# Generated by FakeRAM 2.0
VERSION 5.7 ;
BUSBITCHARS "[]" ;
PROPERTYDEFINITIONS
  MACRO width INTEGER ;
  MACRO depth INTEGER ;
  MACRO banks INTEGER ;
END PROPERTYDEFINITIONS
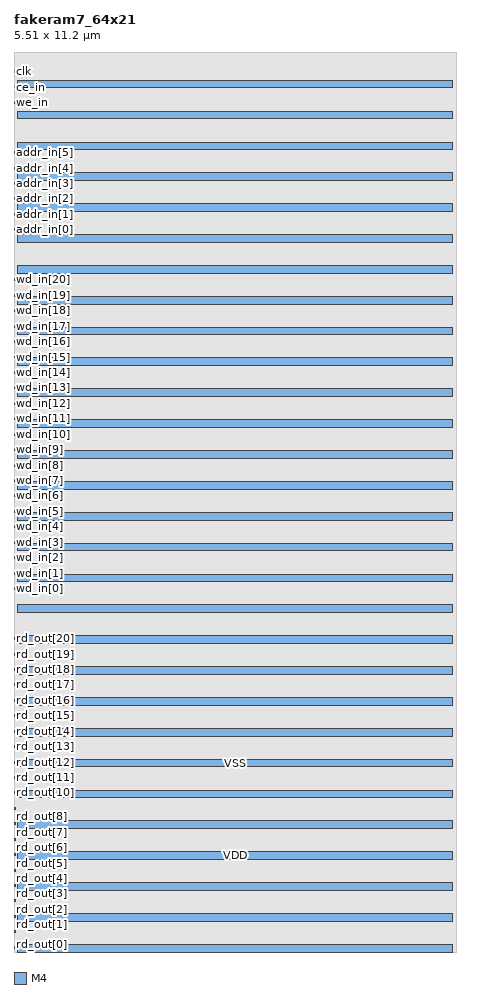
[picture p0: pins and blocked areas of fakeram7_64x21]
MACRO fakeram7_64x21
  PROPERTY width 21 ;
  PROPERTY depth 64 ;
  PROPERTY banks 2 ;
  FOREIGN fakeram7_64x21 0 0 ;
  SYMMETRY X Y R90 ;
  SIZE 5.510 BY 11.200 ;
  CLASS BLOCK ;
  PIN rd_out[0]
    DIRECTION OUTPUT ;
    USE SIGNAL ;
    SHAPE ABUTMENT ;
    PORT
      LAYER M4 ;
      RECT 0.000 0.048 0.024 0.072 ;
    END
  END rd_out[0]
  PIN rd_out[1]
    DIRECTION OUTPUT ;
    USE SIGNAL ;
    SHAPE ABUTMENT ;
    PORT
      LAYER M4 ;
      RECT 0.000 0.240 0.024 0.264 ;
    END
  END rd_out[1]
  PIN rd_out[2]
    DIRECTION OUTPUT ;
    USE SIGNAL ;
    SHAPE ABUTMENT ;
    PORT
      LAYER M4 ;
      RECT 0.000 0.432 0.024 0.456 ;
    END
  END rd_out[2]
  PIN rd_out[3]
    DIRECTION OUTPUT ;
    USE SIGNAL ;
    SHAPE ABUTMENT ;
    PORT
      LAYER M4 ;
      RECT 0.000 0.624 0.024 0.648 ;
    END
  END rd_out[3]
  PIN rd_out[4]
    DIRECTION OUTPUT ;
    USE SIGNAL ;
    SHAPE ABUTMENT ;
    PORT
      LAYER M4 ;
      RECT 0.000 0.816 0.024 0.840 ;
    END
  END rd_out[4]
  PIN rd_out[5]
    DIRECTION OUTPUT ;
    USE SIGNAL ;
    SHAPE ABUTMENT ;
    PORT
      LAYER M4 ;
      RECT 0.000 1.008 0.024 1.032 ;
    END
  END rd_out[5]
  PIN rd_out[6]
    DIRECTION OUTPUT ;
    USE SIGNAL ;
    SHAPE ABUTMENT ;
    PORT
      LAYER M4 ;
      RECT 0.000 1.200 0.024 1.224 ;
    END
  END rd_out[6]
  PIN rd_out[7]
    DIRECTION OUTPUT ;
    USE SIGNAL ;
    SHAPE ABUTMENT ;
    PORT
      LAYER M4 ;
      RECT 0.000 1.392 0.024 1.416 ;
    END
  END rd_out[7]
  PIN rd_out[8]
    DIRECTION OUTPUT ;
    USE SIGNAL ;
    SHAPE ABUTMENT ;
    PORT
      LAYER M4 ;
      RECT 0.000 1.584 0.024 1.608 ;
    END
  END rd_out[8]
  PIN rd_out[9]
    DIRECTION OUTPUT ;
    USE SIGNAL ;
    SHAPE ABUTMENT ;
    PORT
      LAYER M4 ;
      RECT 0.000 1.776 0.024 1.800 ;
    END
  END rd_out[9]
  PIN rd_out[10]
    DIRECTION OUTPUT ;
    USE SIGNAL ;
    SHAPE ABUTMENT ;
    PORT
      LAYER M4 ;
      RECT 0.000 1.968 0.024 1.992 ;
    END
  END rd_out[10]
  PIN rd_out[11]
    DIRECTION OUTPUT ;
    USE SIGNAL ;
    SHAPE ABUTMENT ;
    PORT
      LAYER M4 ;
      RECT 0.000 2.160 0.024 2.184 ;
    END
  END rd_out[11]
  PIN rd_out[12]
    DIRECTION OUTPUT ;
    USE SIGNAL ;
    SHAPE ABUTMENT ;
    PORT
      LAYER M4 ;
      RECT 0.000 2.352 0.024 2.376 ;
    END
  END rd_out[12]
  PIN rd_out[13]
    DIRECTION OUTPUT ;
    USE SIGNAL ;
    SHAPE ABUTMENT ;
    PORT
      LAYER M4 ;
      RECT 0.000 2.544 0.024 2.568 ;
    END
  END rd_out[13]
  PIN rd_out[14]
    DIRECTION OUTPUT ;
    USE SIGNAL ;
    SHAPE ABUTMENT ;
    PORT
      LAYER M4 ;
      RECT 0.000 2.736 0.024 2.760 ;
    END
  END rd_out[14]
  PIN rd_out[15]
    DIRECTION OUTPUT ;
    USE SIGNAL ;
    SHAPE ABUTMENT ;
    PORT
      LAYER M4 ;
      RECT 0.000 2.928 0.024 2.952 ;
    END
  END rd_out[15]
  PIN rd_out[16]
    DIRECTION OUTPUT ;
    USE SIGNAL ;
    SHAPE ABUTMENT ;
    PORT
      LAYER M4 ;
      RECT 0.000 3.120 0.024 3.144 ;
    END
  END rd_out[16]
  PIN rd_out[17]
    DIRECTION OUTPUT ;
    USE SIGNAL ;
    SHAPE ABUTMENT ;
    PORT
      LAYER M4 ;
      RECT 0.000 3.312 0.024 3.336 ;
    END
  END rd_out[17]
  PIN rd_out[18]
    DIRECTION OUTPUT ;
    USE SIGNAL ;
    SHAPE ABUTMENT ;
    PORT
      LAYER M4 ;
      RECT 0.000 3.504 0.024 3.528 ;
    END
  END rd_out[18]
  PIN rd_out[19]
    DIRECTION OUTPUT ;
    USE SIGNAL ;
    SHAPE ABUTMENT ;
    PORT
      LAYER M4 ;
      RECT 0.000 3.696 0.024 3.720 ;
    END
  END rd_out[19]
  PIN rd_out[20]
    DIRECTION OUTPUT ;
    USE SIGNAL ;
    SHAPE ABUTMENT ;
    PORT
      LAYER M4 ;
      RECT 0.000 3.888 0.024 3.912 ;
    END
  END rd_out[20]
  PIN wd_in[0]
    DIRECTION INPUT ;
    USE SIGNAL ;
    SHAPE ABUTMENT ;
    PORT
      LAYER M4 ;
      RECT 0.000 4.512 0.024 4.536 ;
    END
  END wd_in[0]
  PIN wd_in[1]
    DIRECTION INPUT ;
    USE SIGNAL ;
    SHAPE ABUTMENT ;
    PORT
      LAYER M4 ;
      RECT 0.000 4.704 0.024 4.728 ;
    END
  END wd_in[1]
  PIN wd_in[2]
    DIRECTION INPUT ;
    USE SIGNAL ;
    SHAPE ABUTMENT ;
    PORT
      LAYER M4 ;
      RECT 0.000 4.896 0.024 4.920 ;
    END
  END wd_in[2]
  PIN wd_in[3]
    DIRECTION INPUT ;
    USE SIGNAL ;
    SHAPE ABUTMENT ;
    PORT
      LAYER M4 ;
      RECT 0.000 5.088 0.024 5.112 ;
    END
  END wd_in[3]
  PIN wd_in[4]
    DIRECTION INPUT ;
    USE SIGNAL ;
    SHAPE ABUTMENT ;
    PORT
      LAYER M4 ;
      RECT 0.000 5.280 0.024 5.304 ;
    END
  END wd_in[4]
  PIN wd_in[5]
    DIRECTION INPUT ;
    USE SIGNAL ;
    SHAPE ABUTMENT ;
    PORT
      LAYER M4 ;
      RECT 0.000 5.472 0.024 5.496 ;
    END
  END wd_in[5]
  PIN wd_in[6]
    DIRECTION INPUT ;
    USE SIGNAL ;
    SHAPE ABUTMENT ;
    PORT
      LAYER M4 ;
      RECT 0.000 5.664 0.024 5.688 ;
    END
  END wd_in[6]
  PIN wd_in[7]
    DIRECTION INPUT ;
    USE SIGNAL ;
    SHAPE ABUTMENT ;
    PORT
      LAYER M4 ;
      RECT 0.000 5.856 0.024 5.880 ;
    END
  END wd_in[7]
  PIN wd_in[8]
    DIRECTION INPUT ;
    USE SIGNAL ;
    SHAPE ABUTMENT ;
    PORT
      LAYER M4 ;
      RECT 0.000 6.048 0.024 6.072 ;
    END
  END wd_in[8]
  PIN wd_in[9]
    DIRECTION INPUT ;
    USE SIGNAL ;
    SHAPE ABUTMENT ;
    PORT
      LAYER M4 ;
      RECT 0.000 6.240 0.024 6.264 ;
    END
  END wd_in[9]
  PIN wd_in[10]
    DIRECTION INPUT ;
    USE SIGNAL ;
    SHAPE ABUTMENT ;
    PORT
      LAYER M4 ;
      RECT 0.000 6.432 0.024 6.456 ;
    END
  END wd_in[10]
  PIN wd_in[11]
    DIRECTION INPUT ;
    USE SIGNAL ;
    SHAPE ABUTMENT ;
    PORT
      LAYER M4 ;
      RECT 0.000 6.624 0.024 6.648 ;
    END
  END wd_in[11]
  PIN wd_in[12]
    DIRECTION INPUT ;
    USE SIGNAL ;
    SHAPE ABUTMENT ;
    PORT
      LAYER M4 ;
      RECT 0.000 6.816 0.024 6.840 ;
    END
  END wd_in[12]
  PIN wd_in[13]
    DIRECTION INPUT ;
    USE SIGNAL ;
    SHAPE ABUTMENT ;
    PORT
      LAYER M4 ;
      RECT 0.000 7.008 0.024 7.032 ;
    END
  END wd_in[13]
  PIN wd_in[14]
    DIRECTION INPUT ;
    USE SIGNAL ;
    SHAPE ABUTMENT ;
    PORT
      LAYER M4 ;
      RECT 0.000 7.200 0.024 7.224 ;
    END
  END wd_in[14]
  PIN wd_in[15]
    DIRECTION INPUT ;
    USE SIGNAL ;
    SHAPE ABUTMENT ;
    PORT
      LAYER M4 ;
      RECT 0.000 7.392 0.024 7.416 ;
    END
  END wd_in[15]
  PIN wd_in[16]
    DIRECTION INPUT ;
    USE SIGNAL ;
    SHAPE ABUTMENT ;
    PORT
      LAYER M4 ;
      RECT 0.000 7.584 0.024 7.608 ;
    END
  END wd_in[16]
  PIN wd_in[17]
    DIRECTION INPUT ;
    USE SIGNAL ;
    SHAPE ABUTMENT ;
    PORT
      LAYER M4 ;
      RECT 0.000 7.776 0.024 7.800 ;
    END
  END wd_in[17]
  PIN wd_in[18]
    DIRECTION INPUT ;
    USE SIGNAL ;
    SHAPE ABUTMENT ;
    PORT
      LAYER M4 ;
      RECT 0.000 7.968 0.024 7.992 ;
    END
  END wd_in[18]
  PIN wd_in[19]
    DIRECTION INPUT ;
    USE SIGNAL ;
    SHAPE ABUTMENT ;
    PORT
      LAYER M4 ;
      RECT 0.000 8.160 0.024 8.184 ;
    END
  END wd_in[19]
  PIN wd_in[20]
    DIRECTION INPUT ;
    USE SIGNAL ;
    SHAPE ABUTMENT ;
    PORT
      LAYER M4 ;
      RECT 0.000 8.352 0.024 8.376 ;
    END
  END wd_in[20]
  PIN addr_in[0]
    DIRECTION INPUT ;
    USE SIGNAL ;
    SHAPE ABUTMENT ;
    PORT
      LAYER M4 ;
      RECT 0.000 8.976 0.024 9.000 ;
    END
  END addr_in[0]
  PIN addr_in[1]
    DIRECTION INPUT ;
    USE SIGNAL ;
    SHAPE ABUTMENT ;
    PORT
      LAYER M4 ;
      RECT 0.000 9.168 0.024 9.192 ;
    END
  END addr_in[1]
  PIN addr_in[2]
    DIRECTION INPUT ;
    USE SIGNAL ;
    SHAPE ABUTMENT ;
    PORT
      LAYER M4 ;
      RECT 0.000 9.360 0.024 9.384 ;
    END
  END addr_in[2]
  PIN addr_in[3]
    DIRECTION INPUT ;
    USE SIGNAL ;
    SHAPE ABUTMENT ;
    PORT
      LAYER M4 ;
      RECT 0.000 9.552 0.024 9.576 ;
    END
  END addr_in[3]
  PIN addr_in[4]
    DIRECTION INPUT ;
    USE SIGNAL ;
    SHAPE ABUTMENT ;
    PORT
      LAYER M4 ;
      RECT 0.000 9.744 0.024 9.768 ;
    END
  END addr_in[4]
  PIN addr_in[5]
    DIRECTION INPUT ;
    USE SIGNAL ;
    SHAPE ABUTMENT ;
    PORT
      LAYER M4 ;
      RECT 0.000 9.936 0.024 9.960 ;
    END
  END addr_in[5]
  PIN we_in
    DIRECTION INPUT ;
    USE SIGNAL ;
    SHAPE ABUTMENT ;
    PORT
      LAYER M4 ;
      RECT 0.000 10.560 0.024 10.584 ;
    END
  END we_in
  PIN ce_in
    DIRECTION INPUT ;
    USE SIGNAL ;
    SHAPE ABUTMENT ;
    PORT
      LAYER M4 ;
      RECT 0.000 10.752 0.024 10.776 ;
    END
  END ce_in
  PIN clk
    DIRECTION INPUT ;
    USE SIGNAL ;
    SHAPE ABUTMENT ;
    PORT
      LAYER M4 ;
      RECT 0.000 10.944 0.024 10.968 ;
    END
  END clk
  PIN VSS
    DIRECTION INOUT ;
    USE GROUND ;
    PORT
      LAYER M4 ;
      RECT 0.048 0.000 5.462 0.096 ;
      RECT 0.048 0.768 5.462 0.864 ;
      RECT 0.048 1.536 5.462 1.632 ;
      RECT 0.048 2.304 5.462 2.400 ;
      RECT 0.048 3.072 5.462 3.168 ;
      RECT 0.048 3.840 5.462 3.936 ;
      RECT 0.048 4.608 5.462 4.704 ;
      RECT 0.048 5.376 5.462 5.472 ;
      RECT 0.048 6.144 5.462 6.240 ;
      RECT 0.048 6.912 5.462 7.008 ;
      RECT 0.048 7.680 5.462 7.776 ;
      RECT 0.048 8.448 5.462 8.544 ;
      RECT 0.048 9.216 5.462 9.312 ;
      RECT 0.048 9.984 5.462 10.080 ;
      RECT 0.048 10.752 5.462 10.848 ;
    END
  END VSS
  PIN VDD
    DIRECTION INOUT ;
    USE POWER ;
    PORT
      LAYER M4 ;
      RECT 0.048 0.384 5.462 0.480 ;
      RECT 0.048 1.152 5.462 1.248 ;
      RECT 0.048 1.920 5.462 2.016 ;
      RECT 0.048 2.688 5.462 2.784 ;
      RECT 0.048 3.456 5.462 3.552 ;
      RECT 0.048 4.224 5.462 4.320 ;
      RECT 0.048 4.992 5.462 5.088 ;
      RECT 0.048 5.760 5.462 5.856 ;
      RECT 0.048 6.528 5.462 6.624 ;
      RECT 0.048 7.296 5.462 7.392 ;
      RECT 0.048 8.064 5.462 8.160 ;
      RECT 0.048 8.832 5.462 8.928 ;
      RECT 0.048 9.600 5.462 9.696 ;
      RECT 0.048 10.368 5.462 10.464 ;
    END
  END VDD
  OBS
    LAYER M1 ;
    RECT 0 0 5.510 11.200 ;
    LAYER M2 ;
    RECT 0 0 5.510 11.200 ;
    LAYER M3 ;
    RECT 0 0 5.510 11.200 ;
    LAYER M4 ;
    RECT 0 0 5.510 11.200 ;
  END
END fakeram7_64x21

END LIBRARY
